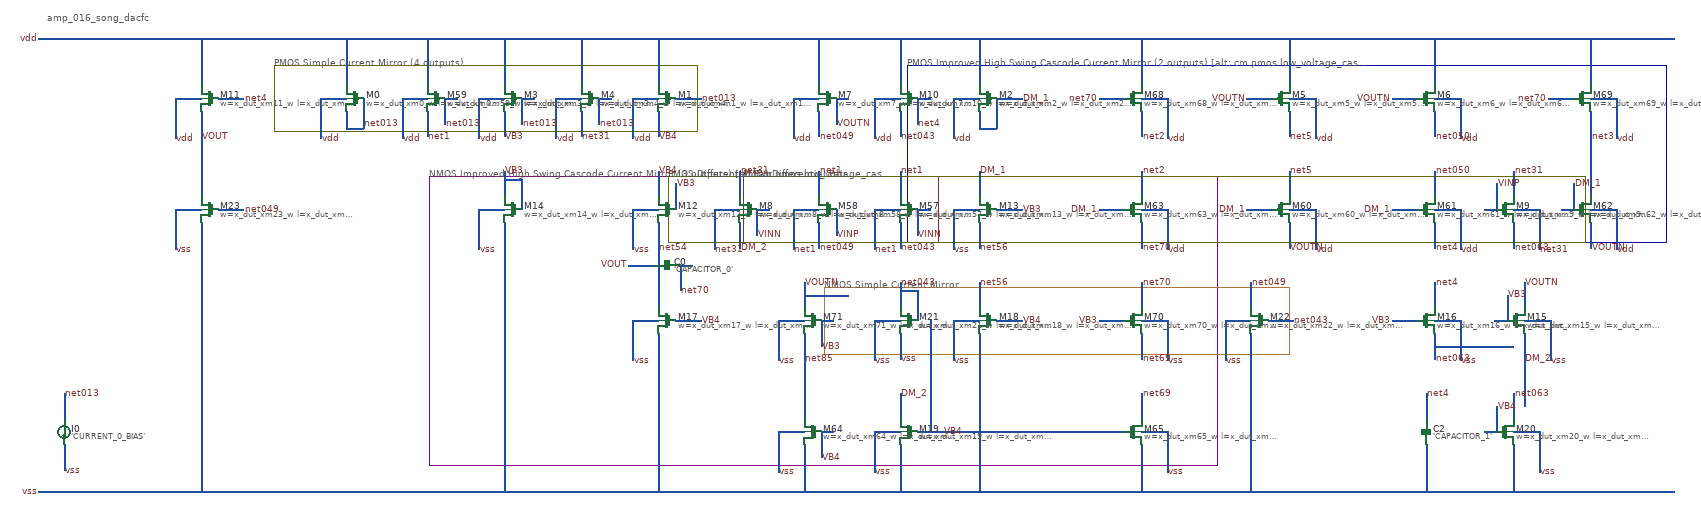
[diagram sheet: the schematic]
v {xschem version=3.4.6 file_version=1.2}
G {}
K {}
V {}
S {}
E {}
T {amp_016_song_dacfc} -1910 -200 0 0 0.4 0.4 {}
C {devices/capa_np.sym} -460 390 1 0 {name=C0 value='CAPACITOR_0'}
C {devices/capa_np.sym} 1315 780 0 0 {name=C2 value='CAPACITOR_1'}
C {devices/isource_np.sym} -1870 780 0 0 {name=I0 value='CURRENT_0_BIAS'}
C {devices/sg13_lv_pmos_np.sym} -1190 0 0 1 {name=M0 model=sg13_lv_pmos spiceprefix=X w=x_dut_xm0_w l=x_dut_xm0_l m=x_dut_xm0_m}
C {devices/sg13_lv_pmos_np.sym} -460 0 0 1 {name=M1 model=sg13_lv_pmos spiceprefix=X w=x_dut_xm1_w l=x_dut_xm1_l m=x_dut_xm1_m}
C {devices/sg13_lv_pmos_np.sym} 105 0 0 1 {name=M10 model=sg13_lv_pmos spiceprefix=X w=x_dut_xm10_w l=x_dut_xm10_l m=x_dut_xm10_m}
C {devices/sg13_lv_pmos_np.sym} -1530 0 0 1 {name=M11 model=sg13_lv_pmos spiceprefix=X w=x_dut_xm11_w l=x_dut_xm11_l m=x_dut_xm11_m}
C {devices/sg13_lv_nmos_np.sym} -460 260 0 1 {name=M12 model=sg13_lv_nmos spiceprefix=X w=x_dut_xm12_w l=x_dut_xm12_l m=x_dut_xm12_m}
C {devices/sg13_lv_nmos_np.sym} 290 260 0 1 {name=M13 model=sg13_lv_nmos spiceprefix=X w=x_dut_xm13_w l=x_dut_xm13_l m=x_dut_xm13_m}
C {devices/sg13_lv_nmos_np.sym} -820 260 0 1 {name=M14 model=sg13_lv_nmos spiceprefix=X w=x_dut_xm14_w l=x_dut_xm14_l m=x_dut_xm14_m}
C {devices/sg13_lv_nmos_np.sym} 1525 520 0 0 {name=M15 model=sg13_lv_nmos spiceprefix=X w=x_dut_xm15_w l=x_dut_xm15_l m=x_dut_xm15_m}
C {devices/sg13_lv_nmos_np.sym} 1315 520 0 0 {name=M16 model=sg13_lv_nmos spiceprefix=X w=x_dut_xm16_w l=x_dut_xm16_l m=x_dut_xm16_m}
C {devices/sg13_lv_nmos_np.sym} -460 520 0 1 {name=M17 model=sg13_lv_nmos spiceprefix=X w=x_dut_xm17_w l=x_dut_xm17_l m=x_dut_xm17_m}
C {devices/sg13_lv_nmos_np.sym} 290 520 0 1 {name=M18 model=sg13_lv_nmos spiceprefix=X w=x_dut_xm18_w l=x_dut_xm18_l m=x_dut_xm18_m}
C {devices/sg13_lv_nmos_np.sym} 105 780 0 1 {name=M19 model=sg13_lv_nmos spiceprefix=X w=x_dut_xm19_w l=x_dut_xm19_l m=x_dut_xm19_m}
C {devices/sg13_lv_pmos_np.sym} 290 0 0 1 {name=M2 model=sg13_lv_pmos spiceprefix=X w=x_dut_xm2_w l=x_dut_xm2_l m=x_dut_xm2_m}
C {devices/sg13_lv_nmos_np.sym} 1500 780 0 0 {name=M20 model=sg13_lv_nmos spiceprefix=X w=x_dut_xm20_w l=x_dut_xm20_l m=x_dut_xm20_m}
C {devices/sg13_lv_nmos_np.sym} 105 520 0 1 {name=M21 model=sg13_lv_nmos spiceprefix=X w=x_dut_xm21_w l=x_dut_xm21_l m=x_dut_xm21_m}
C {devices/sg13_lv_nmos_np.sym} 925 520 0 1 {name=M22 model=sg13_lv_nmos spiceprefix=X w=x_dut_xm22_w l=x_dut_xm22_l m=x_dut_xm22_m}
C {devices/sg13_lv_nmos_np.sym} -1530 260 0 1 {name=M23 model=sg13_lv_nmos spiceprefix=X w=x_dut_xm23_w l=x_dut_xm23_l m=x_dut_xm23_m}
C {devices/sg13_lv_pmos_np.sym} -820 0 0 1 {name=M3 model=sg13_lv_pmos spiceprefix=X w=x_dut_xm3_w l=x_dut_xm3_l m=x_dut_xm3_m}
C {devices/sg13_lv_pmos_np.sym} -640 0 0 1 {name=M4 model=sg13_lv_pmos spiceprefix=X w=x_dut_xm4_w l=x_dut_xm4_l m=x_dut_xm4_m}
C {devices/sg13_lv_pmos_np.sym} 975 0 0 0 {name=M5 model=sg13_lv_pmos spiceprefix=X w=x_dut_xm5_w l=x_dut_xm5_l m=x_dut_xm5_m}
C {devices/sg13_lv_pmos_np.sym} 105 260 0 1 {name=M57 model=sg13_lv_pmos spiceprefix=X w=x_dut_xm57_w l=x_dut_xm57_l m=x_dut_xm57_m}
C {devices/sg13_lv_pmos_np.sym} -85 260 0 1 {name=M58 model=sg13_lv_pmos spiceprefix=X w=x_dut_xm58_w l=x_dut_xm58_l m=x_dut_xm58_m}
C {devices/sg13_lv_pmos_np.sym} -1000 0 0 1 {name=M59 model=sg13_lv_pmos spiceprefix=X w=x_dut_xm59_w l=x_dut_xm59_l m=x_dut_xm59_m}
C {devices/sg13_lv_pmos_np.sym} 1315 0 0 0 {name=M6 model=sg13_lv_pmos spiceprefix=X w=x_dut_xm6_w l=x_dut_xm6_l m=x_dut_xm6_m}
C {devices/sg13_lv_pmos_np.sym} 975 260 0 0 {name=M60 model=sg13_lv_pmos spiceprefix=X w=x_dut_xm60_w l=x_dut_xm60_l m=x_dut_xm60_m}
C {devices/sg13_lv_pmos_np.sym} 1315 260 0 0 {name=M61 model=sg13_lv_pmos spiceprefix=X w=x_dut_xm61_w l=x_dut_xm61_l m=x_dut_xm61_m}
C {devices/sg13_lv_pmos_np.sym} 1680 260 0 0 {name=M62 model=sg13_lv_pmos spiceprefix=X w=x_dut_xm62_w l=x_dut_xm62_l m=x_dut_xm62_m}
C {devices/sg13_lv_pmos_np.sym} 630 260 0 0 {name=M63 model=sg13_lv_pmos spiceprefix=X w=x_dut_xm63_w l=x_dut_xm63_l m=x_dut_xm63_m}
C {devices/sg13_lv_nmos_np.sym} -120 780 0 1 {name=M64 model=sg13_lv_nmos spiceprefix=X w=x_dut_xm64_w l=x_dut_xm64_l m=x_dut_xm64_m}
C {devices/sg13_lv_nmos_np.sym} 630 780 0 0 {name=M65 model=sg13_lv_nmos spiceprefix=X w=x_dut_xm65_w l=x_dut_xm65_l m=x_dut_xm65_m}
C {devices/sg13_lv_pmos_np.sym} 630 0 0 0 {name=M68 model=sg13_lv_pmos spiceprefix=X w=x_dut_xm68_w l=x_dut_xm68_l m=x_dut_xm68_m}
C {devices/sg13_lv_pmos_np.sym} 1680 0 0 0 {name=M69 model=sg13_lv_pmos spiceprefix=X w=x_dut_xm69_w l=x_dut_xm69_l m=x_dut_xm69_m}
C {devices/sg13_lv_pmos_np.sym} -85 0 0 1 {name=M7 model=sg13_lv_pmos spiceprefix=X w=x_dut_xm7_w l=x_dut_xm7_l m=x_dut_xm7_m}
C {devices/sg13_lv_nmos_np.sym} 630 520 0 0 {name=M70 model=sg13_lv_nmos spiceprefix=X w=x_dut_xm70_w l=x_dut_xm70_l m=x_dut_xm70_m}
C {devices/sg13_lv_nmos_np.sym} -120 520 0 1 {name=M71 model=sg13_lv_nmos spiceprefix=X w=x_dut_xm71_w l=x_dut_xm71_l m=x_dut_xm71_m}
C {devices/sg13_lv_pmos_np.sym} -270 260 0 1 {name=M8 model=sg13_lv_pmos spiceprefix=X w=x_dut_xm8_w l=x_dut_xm8_l m=x_dut_xm8_m}
C {devices/sg13_lv_pmos_np.sym} 1500 260 0 0 {name=M9 model=sg13_lv_pmos spiceprefix=X w=x_dut_xm9_w l=x_dut_xm9_l m=x_dut_xm9_m}
N -1870 690 -1870 750 {}
N -1870 810 -1870 870 {}
N -1610 0 -1610 94 {}
N -1610 260 -1610 354 {}
N -1550 -140 -1550 -30 {}
N -1550 30 -1550 230 {}
N -1550 290 -1550 920 {}
N -1270 0 -1270 94 {}
N -1210 -140 -1210 -30 {}
N -1210 30 -1210 70 {}
N -1170 0 -1170 70 {}
N -1080 0 -1080 94 {}
N -1020 -140 -1020 -30 {}
N -1020 30 -1020 90 {}
N -980 0 -980 60 {}
N -900 0 -900 94 {}
N -900 260 -900 354 {}
N -840 -140 -840 -30 {}
N -840 30 -840 90 {}
N -840 170 -840 230 {}
N -840 290 -840 920 {}
N -800 0 -800 60 {}
N -800 190 -800 260 {}
N -720 0 -720 94 {}
N -660 -140 -660 -30 {}
N -660 30 -660 90 {}
N -620 0 -620 60 {}
N -540 0 -540 94 {}
N -540 260 -540 354 {}
N -540 520 -540 614 {}
N -480 -140 -480 -30 {}
N -480 30 -480 90 {}
N -480 170 -480 230 {}
N -480 290 -480 490 {}
N -480 550 -480 920 {}
N -440 200 -440 260 {}
N -430 390 -430 450 {}
N -350 260 -350 354 {}
N -290 170 -290 230 {}
N -290 290 -290 350 {}
N -250 260 -250 320 {}
N -200 520 -200 614 {}
N -200 780 -200 874 {}
N -165 0 -165 94 {}
N -165 260 -165 354 {}
N -140 430 -140 490 {}
N -140 550 -140 750 {}
N -140 810 -140 920 {}
N -105 -140 -105 -30 {}
N -105 30 -105 90 {}
N -105 170 -105 230 {}
N -105 290 -105 350 {}
N -100 520 -100 580 {}
N -100 780 -100 840 {}
N -65 0 -65 60 {}
N -65 260 -65 320 {}
N 25 0 25 94 {}
N 25 260 25 354 {}
N 25 520 25 614 {}
N 25 780 25 874 {}
N 85 -140 85 -30 {}
N 85 30 85 90 {}
N 85 170 85 230 {}
N 85 290 85 350 {}
N 85 430 85 490 {}
N 85 550 85 610 {}
N 85 690 85 750 {}
N 85 810 85 920 {}
N 125 0 125 60 {}
N 125 260 125 320 {}
N 125 450 125 520 {}
N 155 520 155 780 {}
N 210 0 210 94 {}
N 210 260 210 354 {}
N 210 520 210 614 {}
N 270 -140 270 -30 {}
N 270 30 270 70 {}
N 270 170 270 230 {}
N 270 290 270 350 {}
N 270 430 270 490 {}
N 270 550 270 920 {}
N 310 0 310 70 {}
N 650 -140 650 -30 {}
N 650 30 650 90 {}
N 650 170 650 230 {}
N 650 290 650 350 {}
N 650 430 650 490 {}
N 650 550 650 610 {}
N 650 690 650 750 {}
N 650 810 650 920 {}
N 710 0 710 94 {}
N 710 260 710 354 {}
N 710 520 710 614 {}
N 710 780 710 874 {}
N 845 520 845 614 {}
N 905 430 905 490 {}
N 905 550 905 920 {}
N 995 -140 995 -30 {}
N 995 30 995 90 {}
N 995 170 995 230 {}
N 995 290 995 350 {}
N 1055 0 1055 94 {}
N 1055 260 1055 354 {}
N 1315 690 1315 750 {}
N 1315 810 1315 920 {}
N 1335 -140 1335 -30 {}
N 1335 30 1335 90 {}
N 1335 170 1335 230 {}
N 1335 290 1335 350 {}
N 1335 430 1335 490 {}
N 1335 550 1335 610 {}
N 1395 0 1395 94 {}
N 1395 260 1395 354 {}
N 1395 520 1395 614 {}
N 1480 200 1480 260 {}
N 1480 720 1480 780 {}
N 1505 460 1505 520 {}
N 1520 170 1520 230 {}
N 1520 290 1520 350 {}
N 1520 690 1520 750 {}
N 1520 810 1520 920 {}
N 1545 430 1545 490 {}
N 1545 550 1545 720 {}
N 1580 260 1580 354 {}
N 1580 780 1580 874 {}
N 1605 520 1605 614 {}
N 1660 200 1660 260 {}
N 1700 -140 1700 -30 {}
N 1700 30 1700 230 {}
N 1700 290 1700 350 {}
N 1760 0 1760 94 {}
N 1760 260 1760 354 {}
N -1930 -140 1895 -140 {}
N -1610 0 -1550 0 {}
N -1510 0 -1450 0 {}
N -1270 0 -1210 0 {}
N -1080 0 -1020 0 {}
N -980 0 -950 0 {}
N -900 0 -840 0 {}
N -800 0 -770 0 {}
N -720 0 -660 0 {}
N -620 0 -590 0 {}
N -540 0 -480 0 {}
N -440 0 -380 0 {}
N -165 0 -105 0 {}
N -65 0 -35 0 {}
N 25 0 85 0 {}
N 125 0 155 0 {}
N 210 0 270 0 {}
N 310 0 370 0 {}
N 550 0 610 0 {}
N 650 0 710 0 {}
N 895 0 955 0 {}
N 995 0 1055 0 {}
N 1235 0 1295 0 {}
N 1335 0 1395 0 {}
N 1600 0 1660 0 {}
N 1700 0 1760 0 {}
N -1210 70 -1170 70 {}
N 270 70 310 70 {}
N -840 190 -800 190 {}
N -1610 260 -1550 260 {}
N -1510 260 -1450 260 {}
N -900 260 -840 260 {}
N -540 260 -480 260 {}
N -350 260 -290 260 {}
N -250 260 -220 260 {}
N -165 260 -105 260 {}
N 25 260 85 260 {}
N 125 260 155 260 {}
N 210 260 270 260 {}
N 310 260 370 260 {}
N 550 260 610 260 {}
N 650 260 710 260 {}
N 895 260 955 260 {}
N 995 260 1055 260 {}
N 1235 260 1295 260 {}
N 1335 260 1395 260 {}
N 1450 260 1480 260 {}
N 1520 260 1580 260 {}
N 1630 260 1660 260 {}
N 1700 260 1760 260 {}
N -550 390 -490 390 {}
N -430 390 -400 390 {}
N 85 450 125 450 {}
N -140 460 -35 460 {}
N -540 520 -480 520 {}
N -440 520 -380 520 {}
N -200 520 -140 520 {}
N -100 520 -70 520 {}
N 25 520 85 520 {}
N 210 520 270 520 {}
N 310 520 370 520 {}
N 550 520 610 520 {}
N 650 520 710 520 {}
N 845 520 905 520 {}
N 945 520 1005 520 {}
N 1235 520 1295 520 {}
N 1335 520 1395 520 {}
N 1475 520 1505 520 {}
N 1545 520 1605 520 {}
N 1335 580 1520 580 {}
N -200 780 -140 780 {}
N -100 780 -70 780 {}
N 25 780 85 780 {}
N 125 780 610 780 {}
N 650 780 710 780 {}
N 1450 780 1480 780 {}
N 1520 780 1580 780 {}
N -1930 920 1895 920 {}
C {devices/lab_wire.sym} -1930 -140 0 0 {name=l0 lab=vdd}
C {devices/lab_wire.sym} -1930 920 0 0 {name=l1 lab=vss}
C {devices/lab_wire.sym} 370 0 0 1 {name=l2 lab=DM_1}
C {devices/lab_wire.sym} 270 170 0 1 {name=l3 lab=DM_1}
C {devices/lab_wire.sym} 550 260 0 0 {name=l4 lab=DM_1}
C {devices/lab_wire.sym} 895 260 0 0 {name=l5 lab=DM_1}
C {devices/lab_wire.sym} 1235 260 0 0 {name=l6 lab=DM_1}
C {devices/lab_wire.sym} 1660 200 0 1 {name=l7 lab=DM_1}
C {devices/lab_wire.sym} -290 350 2 0 {name=l8 lab=DM_2}
C {devices/lab_wire.sym} 85 690 0 1 {name=l9 lab=DM_2}
C {devices/lab_wire.sym} 1545 610 2 0 {name=l10 lab=DM_2}
C {devices/lab_wire.sym} -840 90 2 0 {name=l11 lab=VB3}
C {devices/lab_wire.sym} -840 170 0 1 {name=l12 lab=VB3}
C {devices/lab_wire.sym} -440 200 0 1 {name=l13 lab=VB3}
C {devices/lab_wire.sym} -100 580 2 0 {name=l14 lab=VB3}
C {devices/lab_wire.sym} 370 260 0 1 {name=l15 lab=VB3}
C {devices/lab_wire.sym} 550 520 0 0 {name=l16 lab=VB3}
C {devices/lab_wire.sym} 1235 520 0 0 {name=l17 lab=VB3}
C {devices/lab_wire.sym} 1505 460 0 1 {name=l18 lab=VB3}
C {devices/lab_wire.sym} -480 90 2 0 {name=l19 lab=VB4}
C {devices/lab_wire.sym} -480 170 0 1 {name=l20 lab=VB4}
C {devices/lab_wire.sym} -380 520 0 1 {name=l21 lab=VB4}
C {devices/lab_wire.sym} -100 840 2 0 {name=l22 lab=VB4}
C {devices/lab_wire.sym} 185 780 0 1 {name=l23 lab=VB4}
C {devices/lab_wire.sym} 370 520 0 1 {name=l24 lab=VB4}
C {devices/lab_wire.sym} 1480 720 0 1 {name=l25 lab=VB4}
C {devices/lab_wire.sym} -250 320 2 0 {name=l26 lab=VINN}
C {devices/lab_wire.sym} 125 320 2 0 {name=l27 lab=VINN}
C {devices/lab_wire.sym} -65 320 2 0 {name=l28 lab=VINP}
C {devices/lab_wire.sym} 1480 200 0 1 {name=l29 lab=VINP}
C {devices/lab_wire.sym} -1550 90 2 0 {name=l30 lab=VOUT}
C {devices/lab_wire.sym} -550 390 0 0 {name=l31 lab=VOUT}
C {devices/lab_wire.sym} -140 430 0 1 {name=l32 lab=VOUTN}
C {devices/lab_wire.sym} -65 60 2 0 {name=l33 lab=VOUTN}
C {devices/lab_wire.sym} 895 0 0 0 {name=l34 lab=VOUTN}
C {devices/lab_wire.sym} 995 350 2 0 {name=l35 lab=VOUTN}
C {devices/lab_wire.sym} 1235 0 0 0 {name=l36 lab=VOUTN}
C {devices/lab_wire.sym} 1545 430 0 1 {name=l37 lab=VOUTN}
C {devices/lab_wire.sym} 1700 350 2 0 {name=l38 lab=VOUTN}
C {devices/lab_wire.sym} -1170 60 2 0 {name=l39 lab=net013}
C {devices/lab_wire.sym} -980 60 2 0 {name=l40 lab=net013}
C {devices/lab_wire.sym} -800 60 2 0 {name=l41 lab=net013}
C {devices/lab_wire.sym} -620 60 2 0 {name=l42 lab=net013}
C {devices/lab_wire.sym} -380 0 0 1 {name=l43 lab=net013}
C {devices/lab_wire.sym} 85 90 2 0 {name=l44 lab=net043}
C {devices/lab_wire.sym} 85 350 2 0 {name=l45 lab=net043}
C {devices/lab_wire.sym} 85 430 0 1 {name=l46 lab=net043}
C {devices/lab_wire.sym} 1005 520 0 1 {name=l47 lab=net043}
C {devices/lab_wire.sym} -1450 260 0 1 {name=l48 lab=net049}
C {devices/lab_wire.sym} -105 90 2 0 {name=l49 lab=net049}
C {devices/lab_wire.sym} -105 350 2 0 {name=l50 lab=net049}
C {devices/lab_wire.sym} 905 430 0 1 {name=l51 lab=net049}
C {devices/lab_wire.sym} 1335 90 2 0 {name=l52 lab=net050}
C {devices/lab_wire.sym} 1335 170 0 1 {name=l53 lab=net050}
C {devices/lab_wire.sym} 1335 610 2 0 {name=l54 lab=net063}
C {devices/lab_wire.sym} 1520 350 2 0 {name=l55 lab=net063}
C {devices/lab_wire.sym} 1520 690 0 1 {name=l56 lab=net063}
C {devices/lab_wire.sym} -1020 90 2 0 {name=l57 lab=net1}
C {devices/lab_wire.sym} -105 170 0 1 {name=l58 lab=net1}
C {devices/lab_wire.sym} 85 170 0 1 {name=l59 lab=net1}
C {devices/lab_wire.sym} 650 90 2 0 {name=l60 lab=net2}
C {devices/lab_wire.sym} 650 170 0 1 {name=l61 lab=net2}
C {devices/lab_wire.sym} 1700 90 2 0 {name=l62 lab=net3}
C {devices/lab_wire.sym} -660 90 2 0 {name=l63 lab=net31}
C {devices/lab_wire.sym} -290 170 0 1 {name=l64 lab=net31}
C {devices/lab_wire.sym} 1520 170 0 1 {name=l65 lab=net31}
C {devices/lab_wire.sym} -1450 0 0 1 {name=l66 lab=net4}
C {devices/lab_wire.sym} 125 60 2 0 {name=l67 lab=net4}
C {devices/lab_wire.sym} 1315 690 0 1 {name=l68 lab=net4}
C {devices/lab_wire.sym} 1335 350 2 0 {name=l69 lab=net4}
C {devices/lab_wire.sym} 1335 430 0 1 {name=l70 lab=net4}
C {devices/lab_wire.sym} 995 90 2 0 {name=l71 lab=net5}
C {devices/lab_wire.sym} 995 170 0 1 {name=l72 lab=net5}
C {devices/lab_wire.sym} -480 350 2 0 {name=l73 lab=net54}
C {devices/lab_wire.sym} 270 350 2 0 {name=l74 lab=net56}
C {devices/lab_wire.sym} 270 430 0 1 {name=l75 lab=net56}
C {devices/lab_wire.sym} 650 610 2 0 {name=l76 lab=net69}
C {devices/lab_wire.sym} 650 690 0 1 {name=l77 lab=net69}
C {devices/lab_wire.sym} -430 450 2 0 {name=l78 lab=net70}
C {devices/lab_wire.sym} 550 0 0 0 {name=l79 lab=net70}
C {devices/lab_wire.sym} 650 350 2 0 {name=l80 lab=net70}
C {devices/lab_wire.sym} 650 430 0 1 {name=l81 lab=net70}
C {devices/lab_wire.sym} 1600 0 0 0 {name=l82 lab=net70}
C {devices/lab_wire.sym} -140 610 2 0 {name=l83 lab=net85}
C {devices/lab_wire.sym} 25 354 2 0 {name=l84 lab=net1}
C {devices/lab_wire.sym} -165 354 2 0 {name=l85 lab=net1}
C {devices/lab_wire.sym} -350 354 2 0 {name=l86 lab=net31}
C {devices/lab_wire.sym} 1580 354 2 0 {name=l87 lab=net31}
C {devices/lab_wire.sym} -1270 94 2 0 {name=l88 lab=vdd}
C {devices/lab_wire.sym} -540 94 2 0 {name=l89 lab=vdd}
C {devices/lab_wire.sym} 25 94 2 0 {name=l90 lab=vdd}
C {devices/lab_wire.sym} -1610 94 2 0 {name=l91 lab=vdd}
C {devices/lab_wire.sym} 210 94 2 0 {name=l92 lab=vdd}
C {devices/lab_wire.sym} -900 94 2 0 {name=l93 lab=vdd}
C {devices/lab_wire.sym} -720 94 2 0 {name=l94 lab=vdd}
C {devices/lab_wire.sym} 1055 94 2 0 {name=l95 lab=vdd}
C {devices/lab_wire.sym} -1080 94 2 0 {name=l96 lab=vdd}
C {devices/lab_wire.sym} 1395 94 2 0 {name=l97 lab=vdd}
C {devices/lab_wire.sym} 1055 354 2 0 {name=l98 lab=vdd}
C {devices/lab_wire.sym} 1395 354 2 0 {name=l99 lab=vdd}
C {devices/lab_wire.sym} 1760 354 2 0 {name=l100 lab=vdd}
C {devices/lab_wire.sym} 710 354 2 0 {name=l101 lab=vdd}
C {devices/lab_wire.sym} 710 94 2 0 {name=l102 lab=vdd}
C {devices/lab_wire.sym} 1760 94 2 0 {name=l103 lab=vdd}
C {devices/lab_wire.sym} -165 94 2 0 {name=l104 lab=vdd}
C {devices/lab_wire.sym} -540 354 2 0 {name=l105 lab=vss}
C {devices/lab_wire.sym} 210 354 2 0 {name=l106 lab=vss}
C {devices/lab_wire.sym} -900 354 2 0 {name=l107 lab=vss}
C {devices/lab_wire.sym} 1605 614 2 0 {name=l108 lab=vss}
C {devices/lab_wire.sym} 1395 614 2 0 {name=l109 lab=vss}
C {devices/lab_wire.sym} -540 614 2 0 {name=l110 lab=vss}
C {devices/lab_wire.sym} 210 614 2 0 {name=l111 lab=vss}
C {devices/lab_wire.sym} 25 874 2 0 {name=l112 lab=vss}
C {devices/lab_wire.sym} 1580 874 2 0 {name=l113 lab=vss}
C {devices/lab_wire.sym} 25 614 2 0 {name=l114 lab=vss}
C {devices/lab_wire.sym} 845 614 2 0 {name=l115 lab=vss}
C {devices/lab_wire.sym} -1610 354 2 0 {name=l116 lab=vss}
C {devices/lab_wire.sym} -200 874 2 0 {name=l117 lab=vss}
C {devices/lab_wire.sym} 710 874 2 0 {name=l118 lab=vss}
C {devices/lab_wire.sym} 710 614 2 0 {name=l119 lab=vss}
C {devices/lab_wire.sym} -200 614 2 0 {name=l120 lab=vss}
C {devices/lab_wire.sym} -1870 870 2 0 {name=l121 lab=vss}
C {devices/lab_wire.sym} -1870 690 0 1 {name=l122 lab=net013}
C {devices/lab_wire.sym} 85 610 2 0 {name=l123 lab=vss}
B 8 -1378 -78 -390 78 {fill=0}
T {PMOS Simple Current Mirror (4 outputs)} -1378 -96 0 0 0.3 0.3 {layer=8}
B 10 -1016 182 826 858 {fill=0}
T {NMOS Improved High Swing Cascode Current Mirror (3 outputs) [alt: cm.nmos.low_voltage_cascode, cm.nmos.low_voltage_cascode, cm.nmos.low_voltage_cascode]} -1016 164 0 0 0.3 0.3 {layer=10}
B 12 102 -78 1876 338 {fill=0}
T {PMOS Improved High Swing Cascode Current Mirror (2 outputs) [alt: cm.pmos.low_voltage_cascode, cm.pmos.low_voltage_cascode]} 102 -96 0 0 0.3 0.3 {layer=12}
B 21 -91 442 995 598 {fill=0}
T {NMOS Simple Current Mirror} -91 424 0 0 0.3 0.3 {layer=21}
B 15 -281 182 175 338 {fill=0}
T {PMOS Differential Pair} -281 164 0 0 0.3 0.3 {layer=15}
B 13 -458 182 1688 338 {fill=0}
T {PMOS Differential Pair} -458 164 0 0 0.3 0.3 {layer=13}
